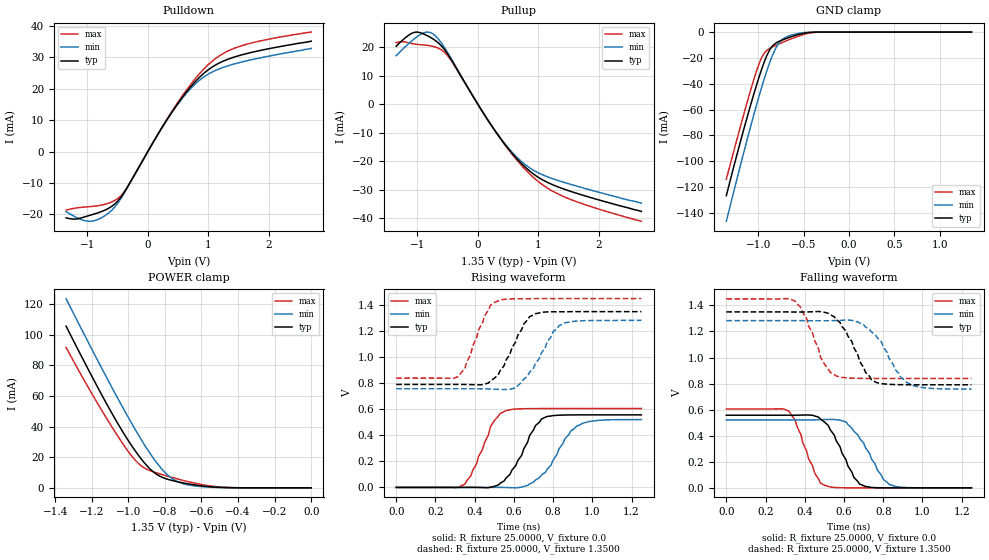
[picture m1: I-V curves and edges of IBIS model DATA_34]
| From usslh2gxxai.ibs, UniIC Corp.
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|When TDQS is enabled, NU_TDQS is a output with terminal resistance;
|When TDQS is disabled, NU_TDQS is a DM;
|   Model DATA_34
[Model]  DATA_34
Model_type I/O
Polarity   Non-Inverting
Enable   Active-High
Vinl =   0.54000000V
Vinh =   0.81000000V
Vmeas =   0.67500000V
Rref =   25.00000000
Vref =   0.67500000V
C_comp   1.6290pF   1.6100pF   1.6540pF
[Temperature Range]   25.0000   95.0000   -40.0
[Voltage Range]   1.3500V   1.2830V   1.4500V
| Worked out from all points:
|   slope of the pulldown table from 0 to 0.203 V, typ, clamps not added: 30.6 ohm
|   slope of the pullup table from 0 to 0.203 V, typ, clamps not added: 29.9 ohm
|   GND clamp passes 1 mA (typ) near -0.50 V on its own axis
|   POWER clamp passes 1 mA (typ) near -0.58 V on its own axis
|   rising waveform, R_fixture 25.0000, V_fixture 0.0: 20-80 % time 118ps typ, 135ps min, 101ps max; typ from 0 V to 0.557 V
|   rising waveform, R_fixture 25.0000, V_fixture 1.3500: 20-80 % time 113ps typ, 123ps min, 96ps max; typ from 0.791 V to 1.35 V
|   falling waveform, R_fixture 25.0000, V_fixture 0.0: 20-80 % time 113ps typ, 123ps min, 91.3ps max; typ from 0.557 V to 0 V
|   falling waveform, R_fixture 25.0000, V_fixture 1.3500: 20-80 % time 116ps typ, 127ps min, 98.9ps max; typ from 1.35 V to 0.791 V
[Pulldown]
|Voltage   I(typ)   I(min)   I(max)
-1.35V    -21.1mA    -19.1mA    -18.6mA
-950mV    -20.24mA   -22.17mA   -17.5mA
-600mV    -17.48mA   -18.77mA   -16.07mA
-450mV    -14.7mA    -15.11mA   -14.18mA
-350mV    -11.73mA   -11.85mA   -11.7mA
150mV     4.943mA    4.94mA     5.014mA
450mV     14mA       13.86mA    14.33mA
750mV     21.51mA    20.87mA    22.36mA
1V        26.03mA    24.64mA    27.65mA
1.25V     28.79mA    26.8mA     31.23mA
1.55V     30.74mA    28.48mA    33.65mA
2.7V      35.1mA     32.8mA     38.01mA
[Pullup]
|Voltage   I(typ)   I(min)   I(max)
-1.35V    20.4mA     17.1mA     21.67mA
-1.05V    25.31mA    23.05mA    21.21mA
-900mV    24.74mA    25.1mA     20.86mA
-750mV    23.1mA     24.86mA    20.41mA
-600mV    20.47mA    21.48mA    19.1mA
-500mV    17.69mA    18.18mA    17.09mA
250mV     -8.265mA   -8.209mA   -8.313mA
500mV     -15.52mA   -15.24mA   -15.77mA
750mV     -21.44mA   -20.63mA   -22.15mA
1.05V     -26.3mA    -24.57mA   -27.98mA
1.35V     -29.2mA    -26.91mA   -31.75mA
2.7V      -37.6mA    -34.7mA    -41.06mA
[GND_clamp]
|Voltage   I(typ)   I(min)   I(max)
-1.35V    -126.6mA   -146.4mA   -113.9mA
-1.23V    -94.01mA   -112.8mA   -82.22mA
-1.11V    -63.21mA   -80.3mA    -51.66mA
-990mV    -34.91mA   -49.67mA   -24.67mA
-930mV    -22.66mA   -35.65mA   -16.03mA
-870mV    -13.47mA   -23.14mA   -12.51mA
-810mV    -8.797mA   -13.1mA    -10.48mA
-780mV    -7.577mA   -9.433mA   -9.536mA
-720mV    -5.772mA   -5.033mA   -7.705mA
-570mV    -2.205mA   -1.261mA   -3.537mA
-360mV    -62.74uA   -23.25uA   -177uA
1.35V     3.66nA     11.73nA    2.588nA
[POWER_clamp]
|Voltage   I(typ)   I(min)   I(max)
-1.34V    105.5mA    123.5mA    91.69mA
-1.14V    59.56mA    76.88mA    49.59mA
-1.06V    42.52mA    58.94mA    34.24mA
-980mV    27.22mA    41.75mA    20.57mA
-940mV    20.5mA     33.6mA     15.4mA
-880mV    12.18mA    22.27mA    11.15mA
-840mV    8.415mA    15.63mA    9.537mA
-780mV    5.408mA    7.848mA    7.429mA
-700mV    3.206mA    2.693mA    4.858mA
-600mV    1.29mA     794.5uA    2.191mA
-440mV    104.5uA    65.08uA    176.8uA
0V        3.66nA     5.436nA    3.157nA
[Ramp]
| variable   typ   min   max
dV/dt_r  0.3343/0.1169n   0.3127/0.1346n   0.3633/99.5040p
dV/dt_f  0.3356/0.1137n   0.3152/0.1290n   0.3664/96.6842p
R_load = 25.0000
[Rising Waveform]
R_fixture= 25.0000
V_fixture= 0.0
V_fixture_min= 0.0
V_fixture_max= 0.0
|time   V(typ)   V(min)   V(max)
0s        0V         0V         0V
350ps     125uV      -9.171uV   25.1mV
410ps     117.4uV    74.84uV    181.9mV
480ps     1.386mV    338.8uV    464.1mV
560ps     71.89mV    -749.3uV   590.4mV
640ps     247.6mV    2.237mV    603.9mV
710ps     474.8mV    56.97mV    605.3mV
760ps     539.1mV    115.7mV    605.5mV
920ps     557mV      470.3mV    605.5mV
1.25ns    557.2mV    521.1mV    605.5mV
[Rising Waveform]
R_fixture= 25.0000
V_fixture= 1.3500
V_fixture_min= 1.2830
V_fixture_max= 1.4500
|time   V(typ)   V(min)   V(max)
0s        790.7mV    757.6mV    839.4mV
320ps     790.8mV    757.6mV    854.2mV
450ps     793mV      756.5mV    1.315V
530ps     897.2mV    752.2mV    1.44V
610ps     1.12V      763.8mV    1.449V
650ps     1.254V     830.7mV    1.449V
710ps     1.334V     952.5mV    1.45V
800ps     1.349V     1.195V     1.45V
860ps     1.349V     1.264V     1.45V
1.25ns    1.35V      1.283V     1.45V
[Falling Waveform]
R_fixture= 25.0000
V_fixture= 0.0
V_fixture_min= 0.0
V_fixture_max= 0.0
|time   V(typ)   V(min)   V(max)
0s        557.2mV    521.1mV    605.5mV
320ps     557.1mV    521mV      586.4mV
350ps     557.3mV    521mV      523.6mV
450ps     551.7mV    521.8mV    115.3mV
500ps     505.5mV    524mV      20.07mV
550ps     405.6mV    524.5mV    3.427mV
610ps     216mV      506mV      351.2uV
680ps     28.48mV    378.3mV    19.89uV
830ps     108.3uV    26.34mV    0V
1.25ns    0V         0V         0V
[Falling Waveform]
R_fixture= 25.0000
V_fixture= 1.3500
V_fixture_min= 1.2830
V_fixture_max= 1.4500
|time   V(typ)   V(min)   V(max)
0s        1.35V      1.283V     1.45V
350ps     1.349V     1.283V     1.434V
410ps     1.35V      1.282V     1.297V
480ps     1.352V     1.282V     1.003V
560ps     1.293V     1.284V     858.4mV
670ps     1.023V     1.274V     840.2mV
710ps     885.4mV    1.234V     839.6mV
760ps     812.2mV    1.175V     839.4mV
920ps     791mV      808mV      839.4mV
1.25ns    790.7mV    757.7mV    839.4mV
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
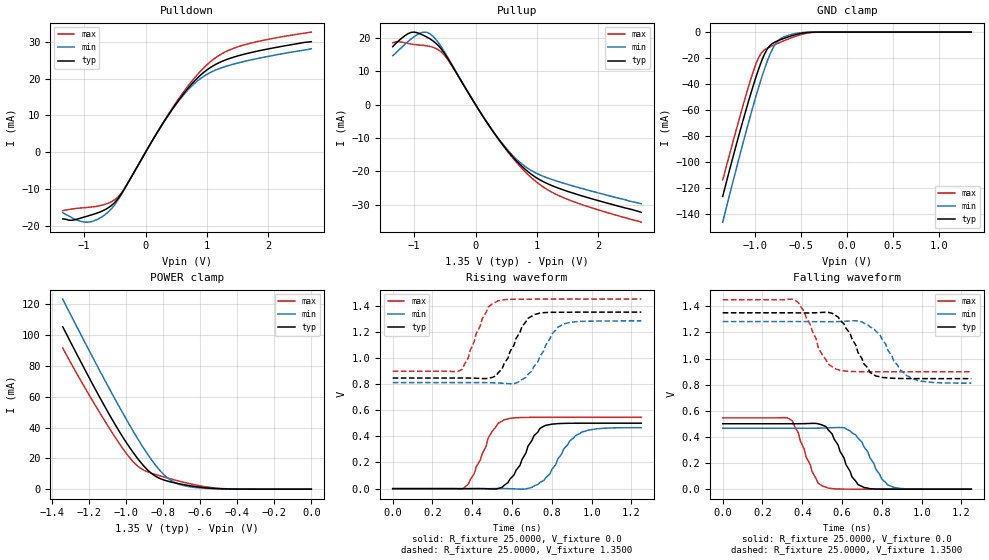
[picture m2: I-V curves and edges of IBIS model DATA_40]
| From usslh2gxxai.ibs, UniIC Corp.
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|   Model DATA_40
[Model]  DATA_40
Model_type I/O
Polarity   Non-Inverting
Enable   Active-High
Vinl =   0.54000000V
Vinh =   0.81000000V
Vmeas =   0.67500000V
Rref =   25.00000000
Vref =   0.67500000V
C_comp   1.6290pF   1.6100pF   1.6540pF
[Temperature Range]   25.0000   95.0000   -40.0
[Voltage Range]   1.3500V   1.2830V   1.4500V
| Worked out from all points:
|   slope of the pulldown table from 0 to 0.203 V, typ, clamps not added: 35.6 ohm
|   slope of the pullup table from 0 to 0.203 V, typ, clamps not added: 34.8 ohm
|   GND clamp passes 1 mA (typ) near -0.50 V on its own axis
|   POWER clamp passes 1 mA (typ) near -0.58 V on its own axis
|   rising waveform, R_fixture 25.0000, V_fixture 0.0: 20-80 % time 102ps typ, 120ps min, 91.5ps max; typ from 0 V to 0.501 V
|   rising waveform, R_fixture 25.0000, V_fixture 1.3500: 20-80 % time 97.2ps typ, 102ps min, 85ps max; typ from 0.846 V to 1.35 V
|   falling waveform, R_fixture 25.0000, V_fixture 0.0: 20-80 % time 93ps typ, 104ps min, 80.7ps max; typ from 0.501 V to 0 V
|   falling waveform, R_fixture 25.0000, V_fixture 1.3500: 20-80 % time 103ps typ, 113ps min, 95.7ps max; typ from 1.35 V to 0.846 V
[Pulldown]
|Voltage   I(typ)   I(min)   I(max)
-1.35V    -18.1mA    -16.4mA    -15.9mA
-1.2V     -18.48mA   -17.8mA    -15.42mA
-950mV    -17.36mA   -19mA      -15mA
-600mV    -15mA      -16.12mA   -13.79mA
-350mV    -10.09mA   -10.2mA    -10.06mA
150mV     4.251mA    4.248mA    4.312mA
450mV     12.04mA    11.91mA    12.32mA
750mV     18.48mA    17.93mA    19.21mA
1V        22.35mA    21.14mA    23.74mA
1.25V     24.7mA     22.99mA    26.8mA
1.5V      26.13mA    24.21mA    28.6mA
2.7V      30mA       28.1mA     32.61mA
[Pullup]
|Voltage   I(typ)   I(min)   I(max)
-1.35V    17.4mA     14.7mA     18.57mA
-1.05V    21.68mA    19.73mA    18.19mA
-900mV    21.23mA    21.49mA    17.88mA
-750mV    19.83mA    21.34mA    17.51mA
-650mV    18.49mA    19.64mA    16.9mA
-500mV    15.23mA    15.64mA    14.69mA
250mV     -7.107mA   -7.058mA   -7.148mA
500mV     -13.34mA   -13.09mA   -13.56mA
750mV     -18.41mA   -17.72mA   -19.03mA
1.05V     -22.57mA   -21.08mA   -24.02mA
1.35V     -25.05mA   -23.08mA   -27.24mA
2.7V      -32.3mA    -29.7mA    -35.26mA
[GND_clamp]
|Voltage   I(typ)   I(min)   I(max)
-1.35V    -126.6mA   -146.4mA   -113.9mA
-1.23V    -94.01mA   -112.8mA   -82.22mA
-1.11V    -63.21mA   -80.3mA    -51.66mA
-990mV    -34.91mA   -49.67mA   -24.67mA
-930mV    -22.66mA   -35.65mA   -16.03mA
-870mV    -13.47mA   -23.14mA   -12.51mA
-810mV    -8.797mA   -13.1mA    -10.48mA
-780mV    -7.577mA   -9.433mA   -9.536mA
-720mV    -5.772mA   -5.033mA   -7.705mA
-570mV    -2.205mA   -1.261mA   -3.537mA
-360mV    -62.74uA   -23.25uA   -177uA
1.35V     3.66nA     11.73nA    2.588nA
[POWER_clamp]
|Voltage   I(typ)   I(min)   I(max)
-1.34V    105.5mA    123.5mA    91.69mA
-1.14V    59.56mA    76.88mA    49.59mA
-1.06V    42.52mA    58.94mA    34.24mA
-980mV    27.22mA    41.75mA    20.57mA
-940mV    20.5mA     33.6mA     15.4mA
-880mV    12.18mA    22.27mA    11.15mA
-840mV    8.415mA    15.63mA    9.537mA
-780mV    5.408mA    7.848mA    7.429mA
-700mV    3.206mA    2.693mA    4.858mA
-600mV    1.29mA     794.5uA    2.191mA
-440mV    104.5uA    65.08uA    176.8uA
0V        3.66nA     5.436nA    3.157nA
[Ramp]
| variable   typ   min   max
dV/dt_r  0.3005/0.1058n   0.2799/0.1203n   0.3274/91.1319p
dV/dt_f  0.3023/0.1041n   0.2831/0.1145n   0.3310/90.9841p
R_load = 25.0000
[Rising Waveform]
R_fixture= 25.0000
V_fixture= 0.0
V_fixture_min= 0.0
V_fixture_max= 0.0
|time   V(typ)   V(min)   V(max)
0s        0V         0V         0V
350ps     -168.2nV   -8.579uV   -3.913mV
410ps     276.8uV    -7.005uV   114.3mV
500ps     -2.724mV   240uV      438.4mV
560ps     24.84mV    483.6uV    526.5mV
640ps     178mV      -3.699mV   543.5mV
710ps     404.5mV    19.98mV    545.5mV
770ps     484.8mV    84.21mV    545.7mV
950ps     500.7mV    432.1mV    545.7mV
1.25ns    500.8mV    466.5mV    545.7mV
[Rising Waveform]
R_fixture= 25.0000
V_fixture= 1.3500
V_fixture_min= 1.2830
V_fixture_max= 1.4500
|time   V(typ)   V(min)   V(max)
0s        846.1mV    811.2mV    898.4mV
350ps     846.3mV    811.2mV    912.8mV
480ps     844.1mV    810.3mV    1.388V
530ps     885.5mV    807.8mV    1.437V
640ps     1.196V     821.1mV    1.449V
680ps     1.303V     873.7mV    1.449V
710ps     1.331V     934mV      1.45V
800ps     1.349V     1.183V     1.45V
860ps     1.349V     1.26V      1.45V
1.25ns    1.35V      1.283V     1.45V
[Falling Waveform]
R_fixture= 25.0000
V_fixture= 0.0
V_fixture_min= 0.0
V_fixture_max= 0.0
|time   V(typ)   V(min)   V(max)
0s        500.8mV    466.5mV    545.7mV
350ps     500.7mV    466.5mV    523.5mV
480ps     499.8mV    467.1mV    45.44mV
530ps     454.8mV    469.3mV    8.298mV
580ps     338.1mV    472mV      1.599mV
650ps     94.15mV    431.4mV    104.9uV
710ps     12.71mV    324.5mV    11.19uV
800ps     404.9uV    76.66mV    0V
860ps     61.5uV     13.66mV    0V
1.25ns    0V         0V         0V
[Falling Waveform]
R_fixture= 25.0000
V_fixture= 1.3500
V_fixture_min= 1.2830
V_fixture_max= 1.4500
|time   V(typ)   V(min)   V(max)
0s        1.35V      1.283V     1.45V
360ps     1.35V      1.283V     1.449V
410ps     1.349V     1.283V     1.361V
530ps     1.353V     1.282V     957.5mV
590ps     1.294V     1.283V     909.4mV
710ps     959.3mV    1.27V      898.8mV
770ps     866.2mV    1.209V     898.5mV
890ps     847.2mV    916.4mV    898.4mV
950ps     846.4mV    846.7mV    898.4mV
1.25ns    846.1mV    811.3mV    898.4mV
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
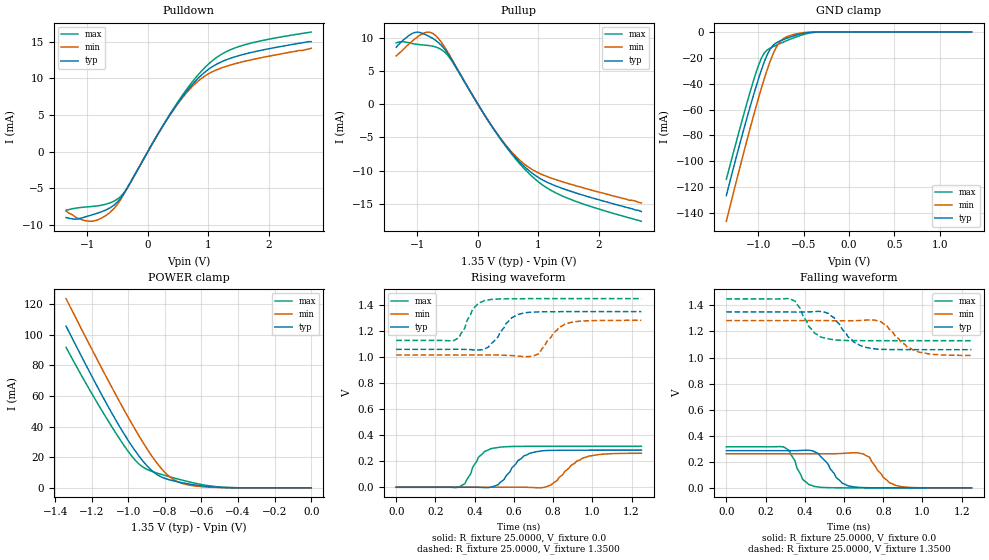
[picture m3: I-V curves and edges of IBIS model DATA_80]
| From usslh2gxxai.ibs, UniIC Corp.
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|   Model DATA_80
[Model]  DATA_80
Model_type I/O
Polarity   Non-Inverting
Enable   Active-High
Vinl =   0.54000000V
Vinh =   0.81000000V
Vmeas =   0.67500000V
Rref =   25.00000000
Vref =   0.67500000V
C_comp   1.6290pF   1.6100pF   1.6540pF
[Temperature Range]   25.0000   95.0000   -40.0
[Voltage Range]   1.3500V   1.2830V   1.4500V
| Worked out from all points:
|   slope of the pulldown table from 0 to 0.203 V, typ, clamps not added: 70.5 ohm
|   slope of the pullup table from 0 to 0.203 V, typ, clamps not added: 69 ohm
|   GND clamp passes 1 mA (typ) near -0.50 V on its own axis
|   POWER clamp passes 1 mA (typ) near -0.58 V on its own axis
|   rising waveform, R_fixture 25.0000, V_fixture 0.0: 20-80 % time 95.1ps typ, 114ps min, 74.2ps max; typ from 0 V to 0.285 V
|   rising waveform, R_fixture 25.0000, V_fixture 1.3500: 20-80 % time 88.7ps typ, 85.8ps min, 65.6ps max; typ from 1.06 V to 1.35 V
|   falling waveform, R_fixture 25.0000, V_fixture 0.0: 20-80 % time 88.5ps typ, 85ps min, 59.4ps max; typ from 0.285 V to 0 V
|   falling waveform, R_fixture 25.0000, V_fixture 1.3500: 20-80 % time 95ps typ, 116ps min, 75.3ps max; typ from 1.35 V to 1.06 V
[Pulldown]
|Voltage   I(typ)   I(min)   I(max)
-1.35V    -9mA       -8.1mA     -8mA
-1.2V     -9.22mA    -8.9mA     -7.72mA
-950mV    -8.7mA     -9.5mA     -7.5mA
-600mV    -7.532mA   -8.104mA   -6.913mA
-350mV    -5.095mA   -5.151mA   -5.075mA
150mV     2.146mA    2.145mA    2.177mA
450mV     6.069mA    6.003mA    6.212mA
750mV     9.3mA      9.014mA    9.676mA
1V        11.22mA    10.61mA    11.93mA
1.25V     12.38mA    11.52mA    13.44mA
1.55V     13.2mA     12.23mA    14.46mA
2.7V      15mA       14.1mA     16.32mA
[Pullup]
|Voltage   I(typ)   I(min)   I(max)
-1.35V    8.6mA      7.3mA      9.27mA
-1.05V    10.82mA    9.81mA     9.1mA
-900mV    10.64mA    10.72mA    8.94mA
-750mV    9.959mA    10.72mA    8.768mA
-650mV    9.3mA      9.895mA    8.473mA
-500mV    7.685mA    7.906mA    7.405mA
250mV     -3.587mA   -3.562mA   -3.608mA
500mV     -6.724mA   -6.596mA   -6.835mA
750mV     -9.264mA   -8.906mA   -9.58mA
1.05V     -11.33mA   -10.57mA   -12.07mA
1.4V      -12.72mA   -11.71mA   -13.87mA
2.7V      -16.2mA    -14.9mA    -17.66mA
[GND_clamp]
|Voltage   I(typ)   I(min)   I(max)
-1.35V    -126.6mA   -146.4mA   -113.9mA
-1.23V    -94.01mA   -112.8mA   -82.22mA
-1.11V    -63.21mA   -80.3mA    -51.66mA
-990mV    -34.91mA   -49.67mA   -24.67mA
-930mV    -22.66mA   -35.65mA   -16.03mA
-870mV    -13.47mA   -23.14mA   -12.51mA
-810mV    -8.797mA   -13.1mA    -10.48mA
-780mV    -7.577mA   -9.433mA   -9.536mA
-720mV    -5.772mA   -5.033mA   -7.705mA
-570mV    -2.205mA   -1.261mA   -3.537mA
-360mV    -62.74uA   -23.25uA   -177uA
1.35V     3.66nA     11.73nA    2.588nA
[POWER_clamp]
|Voltage   I(typ)   I(min)   I(max)
-1.34V    105.5mA    123.5mA    91.69mA
-1.14V    59.56mA    76.88mA    49.59mA
-1.06V    42.52mA    58.94mA    34.24mA
-980mV    27.22mA    41.75mA    20.57mA
-940mV    20.5mA     33.6mA     15.4mA
-880mV    12.18mA    22.27mA    11.15mA
-840mV    8.415mA    15.63mA    9.537mA
-780mV    5.408mA    7.848mA    7.429mA
-700mV    3.206mA    2.693mA    4.858mA
-600mV    1.29mA     794.5uA    2.191mA
-440mV    104.5uA    65.08uA    176.8uA
0V        3.66nA     5.436nA    3.157nA
[Ramp]
| variable   typ   min   max
dV/dt_r  0.1711/95.8702p   0.1568/0.1150n   0.1889/70.6281p
dV/dt_f  0.1740/97.5000p   0.1602/0.1134n   0.1926/76.8497p
R_load = 25.0000
[Rising Waveform]
R_fixture= 25.0000
V_fixture= 0.0
V_fixture_min= 0.0
V_fixture_max= 0.0
|time   V(typ)   V(min)   V(max)
0s        0V         0V         0V
320ps     28.4uV     0V         566.4uV
350ps     147.1uV    0V         27.35mV
420ps     -395uV     -6.871uV   231.9mV
500ps     7.999mV    19.25uV    301.7mV
620ps     203.4mV    449.6uV    314.2mV
710ps     272.5mV    -3.187mV   314.8mV
790ps     283.4mV    17.6mV     314.9mV
980ps     285mV      238.6mV    314.9mV
1.25ns    285.1mV    261.3mV    314.9mV
[Rising Waveform]
R_fixture= 25.0000
V_fixture= 1.3500
V_fixture_min= 1.2830
V_fixture_max= 1.4500
|time   V(typ)   V(min)   V(max)
0s        1.06V      1.016V     1.129V
290ps     1.061V     1.016V     1.126V
320ps     1.061V     1.016V     1.15V
390ps     1.056V     1.016V     1.37V
480ps     1.097V     1.016V     1.443V
590ps     1.304V     1.012V     1.449V
650ps     1.34V      1.004V     1.449V
730ps     1.348V     1.028V     1.45V
860ps     1.35V      1.254V     1.45V
1.25ns    1.35V      1.283V     1.45V
[Falling Waveform]
R_fixture= 25.0000
V_fixture= 0.0
V_fixture_min= 0.0
V_fixture_max= 0.0
|time   V(typ)   V(min)   V(max)
0s        285.1mV    261.4mV    314.9mV
290ps     285mV      261.4mV    315mV
320ps     284.8mV    261.4mV    287.5mV
390ps     287.8mV    261.3mV    63.36mV
450ps     276.3mV    261.2mV    10.3mV
620ps     15.58mV    267.3mV    71.96uV
730ps     785.6uV    235.2mV    2.735uV
800ps     64.2uV     80.46mV    0V
860ps     11.7uV     19.72mV    0V
1.25ns    0V         0V         0V
[Falling Waveform]
R_fixture= 25.0000
V_fixture= 1.3500
V_fixture_min= 1.2830
V_fixture_max= 1.4500
|time   V(typ)   V(min)   V(max)
0s        1.35V      1.283V     1.45V
320ps     1.35V      1.283V     1.452V
350ps     1.349V     1.283V     1.433V
450ps     1.353V     1.283V     1.187V
530ps     1.324V     1.282V     1.14V
650ps     1.118V     1.283V     1.13V
710ps     1.078V     1.287V     1.129V
790ps     1.063V     1.273V     1.129V
980ps     1.06V      1.042V     1.129V
1.25ns    1.06V      1.016V     1.129V
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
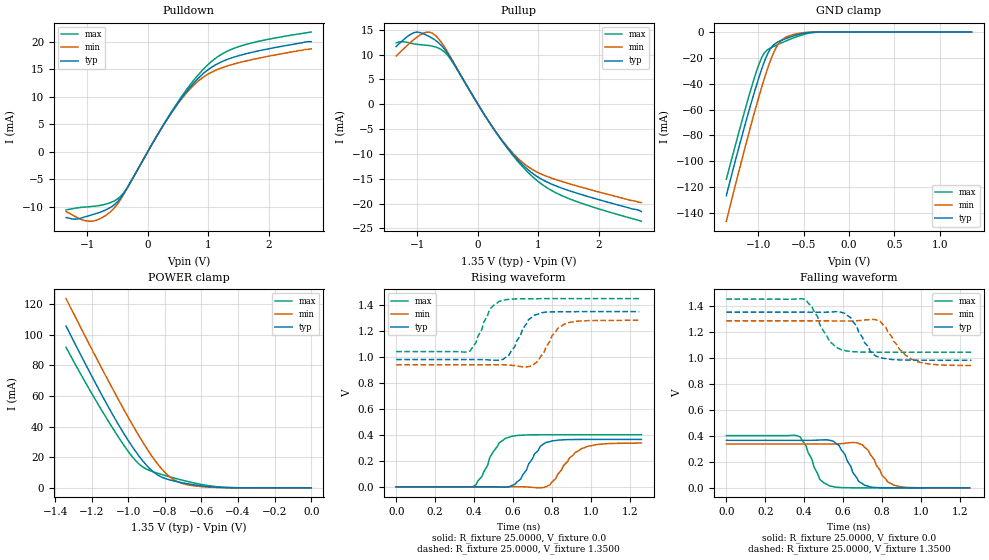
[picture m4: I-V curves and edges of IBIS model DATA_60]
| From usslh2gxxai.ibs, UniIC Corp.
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|   Model DATA_60
[Model]  DATA_60
Model_type I/O
Polarity   Non-Inverting
Enable   Active-High
Vinl =   0.54000000V
Vinh =   0.81000000V
Vmeas =   0.67500000V
Rref =   25.00000000
Vref =   0.67500000V
C_comp   1.6290pF   1.6100pF   1.6540pF
[Temperature Range]   25.0000   95.0000   -40.0
[Voltage Range]   1.3500V   1.2830V   1.4500V
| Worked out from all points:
|   slope of the pulldown table from 0 to 0.203 V, typ, clamps not added: 53.1 ohm
|   slope of the pullup table from 0 to 0.203 V, typ, clamps not added: 51.9 ohm
|   GND clamp passes 1 mA (typ) near -0.50 V on its own axis
|   POWER clamp passes 1 mA (typ) near -0.58 V on its own axis
|   rising waveform, R_fixture 25.0000, V_fixture 0.0: 20-80 % time 89.5ps typ, 106ps min, 82.8ps max; typ from 0 V to 0.365 V
|   rising waveform, R_fixture 25.0000, V_fixture 1.3500: 20-80 % time 80.5ps typ, 82.1ps min, 68.4ps max; typ from 0.98 V to 1.35 V
|   falling waveform, R_fixture 25.0000, V_fixture 0.0: 20-80 % time 81.1ps typ, 84.2ps min, 66.2ps max; typ from 0.365 V to 0 V
|   falling waveform, R_fixture 25.0000, V_fixture 1.3500: 20-80 % time 86.7ps typ, 107ps min, 84.3ps max; typ from 1.35 V to 0.98 V
[Pulldown]
|Voltage   I(typ)   I(min)   I(max)
-1.35V    -12mA      -10.9mA    -10.6mA
-1.2V     -12.29mA   -11.8mA    -10.29mA
-950mV    -11.59mA   -12.67mA   -10mA
-600mV    -10.03mA   -10.79mA   -9.203mA
-450mV    -8.463mA   -8.711mA   -8.15mA
-350mV    -6.771mA   -6.844mA   -6.746mA
150mV     2.852mA    2.85mA     2.893mA
450mV     8.069mA    7.982mA    8.258mA
750mV     12.37mA    12mA       12.87mA
1V        14.94mA    14.13mA    15.88mA
1.5V      17.44mA    16.16mA    19.09mA
2.7V      20mA       18.7mA     21.75mA
[Pullup]
|Voltage   I(typ)   I(min)   I(max)
-1.35V    11.6mA     9.7mA      12.37mA
-1.05V    14.44mA    13.1mA     12.13mA
-900mV    14.18mA    14.31mA    11.92mA
-750mV    13.26mA    14.27mA    11.68mA
-650mV    12.37mA    13.16mA    11.29mA
-500mV    10.22mA    10.5mA     9.845mA
250mV     -4.768mA   -4.734mA   -4.796mA
500mV     -8.941mA   -8.773mA   -9.088mA
750mV     -12.33mA   -11.85mA   -12.74mA
1.05V     -15.08mA   -14.08mA   -16.06mA
1.4V      -16.95mA   -15.6mA    -18.47mA
2.7V      -21.6mA    -19.8mA    -23.56mA
[GND_clamp]
|Voltage   I(typ)   I(min)   I(max)
-1.35V    -126.6mA   -146.4mA   -113.9mA
-1.23V    -94.01mA   -112.8mA   -82.22mA
-1.11V    -63.21mA   -80.3mA    -51.66mA
-990mV    -34.91mA   -49.67mA   -24.67mA
-930mV    -22.66mA   -35.65mA   -16.03mA
-870mV    -13.47mA   -23.14mA   -12.51mA
-810mV    -8.797mA   -13.1mA    -10.48mA
-780mV    -7.577mA   -9.433mA   -9.536mA
-720mV    -5.772mA   -5.033mA   -7.705mA
-570mV    -2.205mA   -1.261mA   -3.537mA
-360mV    -62.74uA   -23.25uA   -177uA
1.35V     3.66nA     11.73nA    2.588nA
[POWER_clamp]
|Voltage   I(typ)   I(min)   I(max)
-1.34V    105.5mA    123.5mA    91.69mA
-1.14V    59.56mA    76.88mA    49.59mA
-1.06V    42.52mA    58.94mA    34.24mA
-980mV    27.22mA    41.75mA    20.57mA
-940mV    20.5mA     33.6mA     15.4mA
-880mV    12.18mA    22.27mA    11.15mA
-840mV    8.415mA    15.63mA    9.537mA
-780mV    5.408mA    7.848mA    7.429mA
-700mV    3.206mA    2.693mA    4.858mA
-600mV    1.29mA     794.5uA    2.191mA
-440mV    104.5uA    65.08uA    176.8uA
0V        3.66nA     5.436nA    3.157nA
[Ramp]
| variable   typ   min   max
dV/dt_r  0.2191/91.3875p   0.2020/0.1080n   0.2408/79.1756p
dV/dt_f  0.2217/91.5243p   0.2057/0.1059n   0.2448/80.6023p
R_load = 25.0000
[Rising Waveform]
R_fixture= 25.0000
V_fixture= 0.0
V_fixture_min= 0.0
V_fixture_max= 0.0
|time   V(typ)   V(min)   V(max)
0s        0V         0V         0V
390ps     -5.094uV   -1.669uV   -2.276mV
440ps     146.2uV    -14.92uV   78.02mV
530ps     -1.175mV   82.15uV    339.7mV
580ps     524.6uV    386.4uV    382mV
640ps     59.46mV    491.2uV    397.2mV
710ps     251.2mV    -5.999mV   400.7mV
760ps     332.9mV    -5.287mV   401.2mV
950ps     364.8mV    292.9mV    401.3mV
1.26ns    365.2mV    337.3mV    401.3mV
[Rising Waveform]
R_fixture= 25.0000
V_fixture= 1.3500
V_fixture_min= 1.2830
V_fixture_max= 1.4500
|time   V(typ)   V(min)   V(max)
0s        980.5mV    940mV      1.042V
380ps     980.6mV    940mV      1.047V
480ps     977mV      940.4mV    1.367V
560ps     994.6mV    939.4mV    1.441V
610ps     1.081V     934.2mV    1.447V
680ps     1.288V     925.9mV    1.449V
740ps     1.339V     998.6mV    1.45V
800ps     1.348V     1.162V     1.45V
860ps     1.349V     1.251V     1.45V
1.25ns    1.35V      1.283V     1.45V
[Falling Waveform]
R_fixture= 25.0000
V_fixture= 0.0
V_fixture_min= 0.0
V_fixture_max= 0.0
|time   V(typ)   V(min)   V(max)
0s        365.2mV    336.7mV    401.3mV
380ps     365.1mV    336.7mV    391.2mV
480ps     367.6mV    336.3mV    65.15mV
530ps     365.8mV    336.1mV    14.79mV
580ps     324mV      337.9mV    3.433mV
650ps     117.8mV    348.4mV    303.5uV
710ps     20.31mV    312.6mV    42.89uV
800ps     868uV      97.17mV    1.055uV
860ps     145.1uV    20.6mV     0V
1.25ns    0V         0V         0V
[Falling Waveform]
R_fixture= 25.0000
V_fixture= 1.3500
V_fixture_min= 1.2830
V_fixture_max= 1.4500
|time   V(typ)   V(min)   V(max)
0s        1.35V      1.283V     1.45V
410ps     1.35V      1.283V     1.444V
530ps     1.351V     1.283V     1.125V
590ps     1.349V     1.282V     1.062V
640ps     1.306V     1.282V     1.048V
760ps     1.022V     1.294V     1.042V
820ps     992.3mV    1.233V     1.042V
890ps     982.8mV    1.064V     1.042V
950ps     981.1mV    988.9mV    1.042V
1.26ns    980.5mV    940.1mV    1.042V
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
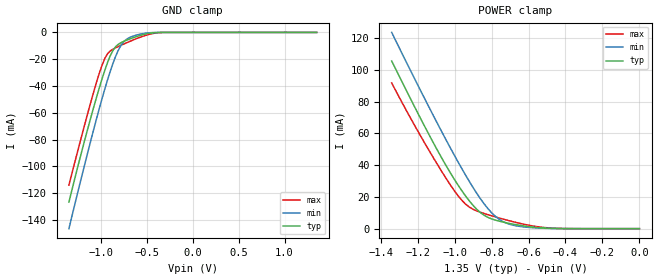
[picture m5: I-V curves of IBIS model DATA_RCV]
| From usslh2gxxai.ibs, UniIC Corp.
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|   Model DATA_RCV
[Model]  DATA_RCV
Model_type Input
Vinl =   0.54000000V
Vinh =   0.81000000V
C_comp   1.6290pF   1.6100pF   1.6540pF
[Temperature Range]   25.0000   95.0000   -40.0
[Voltage Range]   1.3500V   1.2830V   1.4500V
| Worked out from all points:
|   GND clamp passes 1 mA (typ) near -0.50 V on its own axis
|   POWER clamp passes 1 mA (typ) near -0.58 V on its own axis
[GND_clamp]
|Voltage   I(typ)   I(min)   I(max)
-1.35V    -126.6mA   -146.4mA   -113.9mA
-1.23V    -94.01mA   -112.8mA   -82.22mA
-1.11V    -63.21mA   -80.3mA    -51.66mA
-990mV    -34.91mA   -49.67mA   -24.67mA
-930mV    -22.66mA   -35.65mA   -16.03mA
-870mV    -13.47mA   -23.14mA   -12.51mA
-810mV    -8.797mA   -13.1mA    -10.48mA
-780mV    -7.577mA   -9.433mA   -9.536mA
-720mV    -5.772mA   -5.033mA   -7.705mA
-570mV    -2.205mA   -1.261mA   -3.537mA
-360mV    -62.74uA   -23.25uA   -177uA
1.35V     3.66nA     11.73nA    2.588nA
[POWER_clamp]
|Voltage   I(typ)   I(min)   I(max)
-1.34V    105.5mA    123.5mA    91.69mA
-1.14V    59.56mA    76.88mA    49.59mA
-1.06V    42.52mA    58.94mA    34.24mA
-980mV    27.22mA    41.75mA    20.57mA
-940mV    20.5mA     33.6mA     15.4mA
-880mV    12.18mA    22.27mA    11.15mA
-840mV    8.415mA    15.63mA    9.537mA
-780mV    5.408mA    7.848mA    7.429mA
-700mV    3.206mA    2.693mA    4.858mA
-600mV    1.29mA     794.5uA    2.191mA
-440mV    104.5uA    65.08uA    176.8uA
0V        3.66nA     5.436nA    3.157nA
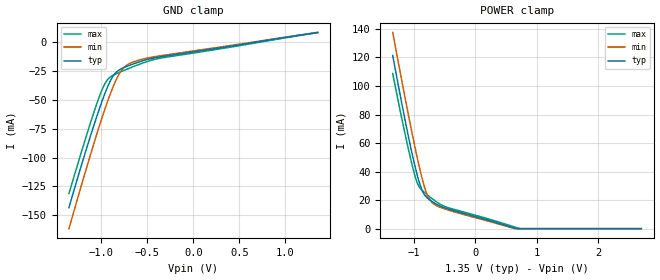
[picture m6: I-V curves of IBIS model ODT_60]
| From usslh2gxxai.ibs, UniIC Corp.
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|   Model ODT_60
[Model]  ODT_60
Model_type Input
Vinl =   0.54000000V
Vinh =   0.81000000V
C_comp   1.6290pF   1.6100pF   1.6540pF
[Temperature Range]   25.0000   95.0000   -40.0
[Voltage Range]   1.3500V   1.2800V   1.4500V
[GND_clamp]
|Voltage   I(typ)   I(min)   I(max)
-1.35V    -143.4mA   -161.6mA   -131.1mA
-1.23V    -110.7mA   -128.2mA   -99.14mA
-1.11V    -79.66mA   -95.84mA   -68.28mA
-990mV    -50.97mA   -65.2mA    -41.03mA
-930mV    -38.52mA   -51.1mA    -32.26mA
-870mV    -29.14mA   -38.44mA   -28.6mA
-810mV    -24.26mA   -28.19mA   -26.42mA
-780mV    -22.93mA   -24.4mA    -25.4mA
-720mV    -20.89mA   -19.73mA   -23.39mA
-570mV    -16.6mA    -15.05mA   -18.67mA
-360mV    -12.67mA   -11.75mA   -13.84mA
1.35V     8.47mA     8.53mA     8.249mA
[POWER_clamp]
|Voltage   I(typ)   I(min)   I(max)
-1.34V    121.4mA    137.6mA    108.8mA
-1.1V     67.77mA    83.12mA    58.68mA
-1.02V    51.59mA    65.83mA    43.79mA
-960mV    40.68mA    53.44mA    34.4mA
-920mV    34.24mA    45.6mA     30.12mA
-880mV    28.83mA    38.26mA    27.66mA
-800mV    22.5mA     26.06mA    24.5mA
-740mV    20.27mA    20.35mA    22.37mA
-680mV    18.51mA    17.5mA     20.36mA
-440mV    13.79mA    13.04mA    14.74mA
675mV     0A         NA         NA
2.7V      0A         0A         0A
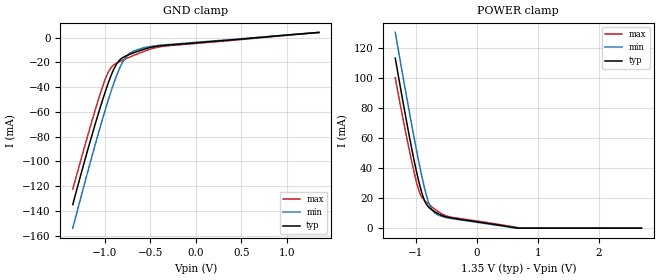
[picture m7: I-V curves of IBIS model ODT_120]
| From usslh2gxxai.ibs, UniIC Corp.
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|   Model ODT_120
[Model]  ODT_120
Model_type Input
Vinl =   0.54000000V
Vinh =   0.81000000V
C_comp   1.6290pF   1.6100pF   1.6540pF
[Temperature Range]   25.0000   95.0000   -40.0
[Voltage Range]   1.3500V   1.2830V   1.4500V
[GND_clamp]
|Voltage   I(typ)   I(min)   I(max)
-1.35V    -135mA     -154mA     -122.5mA
-1.11V    -71.44mA   -88.11mA   -59.98mA
-1.05V    -56.79mA   -72.47mA   -45.59mA
-990mV    -42.94mA   -57.47mA   -32.86mA
-930mV    -30.6mA    -43.41mA   -24.14mA
-870mV    -21.31mA   -30.83mA   -20.56mA
-810mV    -16.53mA   -20.68mA   -18.45mA
-780mV    -15.26mA   -16.96mA   -17.47mA
-720mV    -13.34mA   -12.42mA   -15.55mA
-570mV    -9.41mA    -8.197mA   -11.11mA
-360mV    -6.373mA   -5.927mA   -7.017mA
1.35V     4.238mA    4.275mA    4.127mA
[POWER_clamp]
|Voltage   I(typ)   I(min)   I(max)
-1.34V    113.4mA    130.6mA    100.3mA
-1.12V    63.6mA     79.97mA    54.13mA
-1.02V    43.09mA    58.06mA    35.43mA
-960mV    32.23mA    45.56mA    26.09mA
-920mV    25.85mA    37.67mA    21.83mA
-880mV    20.51mA    30.29mA    19.41mA
-800mV    14.34mA    18.1mA     16.31mA
-740mV    12.25mA    12.5mA     14.24mA
-680mV    10.64mA    9.841mA    12.32mA
-440mV    6.958mA    6.593mA    7.468mA
675mV     0A         NA         NA
2.7V      0A         0A         0A
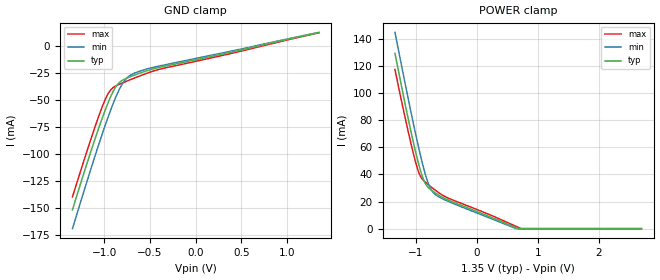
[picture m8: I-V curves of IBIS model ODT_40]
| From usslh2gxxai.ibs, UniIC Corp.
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|   Model ODT_40
[Model]  ODT_40
Model_type Input
Vinl =   0.54000000V
Vinh =   0.81000000V
C_comp   1.6290pF   1.6100pF   1.6540pF
[Temperature Range]   25.0000   95.0000   -40.0
[Voltage Range]   1.3500V   1.2830V   1.4500V
[GND_clamp]
|Voltage   I(typ)   I(min)   I(max)
-1.35V    -151.8mA   -169.3mA   -139.8mA
-1.2V     -111.1mA   -127.9mA   -99.69mA
-1.11V    -87.88mA   -103.7mA   -76.58mA
-1.05V    -73.03mA   -88.1mA    -62.06mA
-990mV    -58.98mA   -73.07mA   -49.2mA
-930mV    -46.44mA   -58.92mA   -40.36mA
-870mV    -36.95mA   -46.18mA   -36.63mA
-810mV    -31.97mA   -35.83mA   -34.38mA
-750mV    -29.46mA   -29.14mA   -32.26mA
-660mV    -26.49mA   -24.63mA   -29.17mA
-450mV    -20.72mA   -19.34mA   -22.7mA
1.35V     12.7mA     12.8mA     12.37mA
[POWER_clamp]
|Voltage   I(typ)   I(min)   I(max)
-1.34V    129.3mA    144.8mA    117.4mA
-1.1V     76.21mA    90.87mA    67.12mA
-1.02V    60.08mA    73.74mA    52.14mA
-960mV    49.12mA    61.45mA    42.71mA
-920mV    42.63mA    53.66mA    38.4mA
-880mV    37.14mA    46.35mA    35.91mA
-800mV    30.66mA    34.12mA    32.68mA
-740mV    28.29mA    28.3mA     30.49mA
-680mV    26.36mA    25.27mA    28.4mA
-460mV    20.99mA    19.97mA    22.39mA
675mV     0A         NA         NA
2.7V      0A         0A         0A
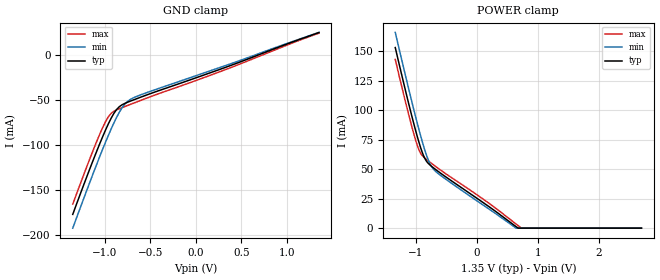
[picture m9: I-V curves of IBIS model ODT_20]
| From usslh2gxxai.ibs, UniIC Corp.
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|   Model ODT_20
[Model]  ODT_20
Model_type Input
Vinl =   0.54000000V
Vinh =   0.81000000V
C_comp   1.6290pF   1.6100pF   1.6540pF
[Temperature Range]   25.0000   95.0000   -40.0
[Voltage Range]   1.3500V   1.2830V   1.4500V
[GND_clamp]
|Voltage   I(typ)   I(min)   I(max)
-1.35V    -176.9mA   -192.2mA   -165.5mA
-1.11V    -112.5mA   -127.1mA   -101.4mA
-1.05V    -97.31mA   -111.5mA   -86.71mA
-990mV    -82.97mA   -96.44mA   -73.67mA
-930mV    -70.13mA   -82.14mA   -64.62mA
-870mV    -60.35mA   -69.15mA   -60.69mA
-810mV    -55.06mA   -58.46mA   -58.2mA
-750mV    -52.21mA   -51.37mA   -55.83mA
-690mV    -49.83mA   -47.52mA   -53.47mA
-540mV    -44.11mA   -41.53mA   -47.63mA
300mV     -14.29mA   -12.27mA   -16.84mA
1.35V     25.34mA    25.54mA    24.69mA
[POWER_clamp]
|Voltage   I(typ)   I(min)   I(max)
-1.34V    153.2mA    166.1mA    143.2mA
-1.1V     101.6mA    114mA      92.39mA
-1.02V    85.55mA    97.33mA    77.18mA
-960mV    74.41mA    85.32mA    67.61mA
-920mV    67.71mA    77.67mA    63.21mA
-880mV    62.01mA    70.43mA    60.64mA
-800mV    55.04mA    58.09mA    57.2mA
-740mV    52.26mA    51.89mA    54.81mA
-640mV    48.29mA    46.49mA    50.91mA
200mV     18.16mA    16.15mA    21.03mA
674.9mV   0A         NA         NA
2.7V      0A         0A         0A
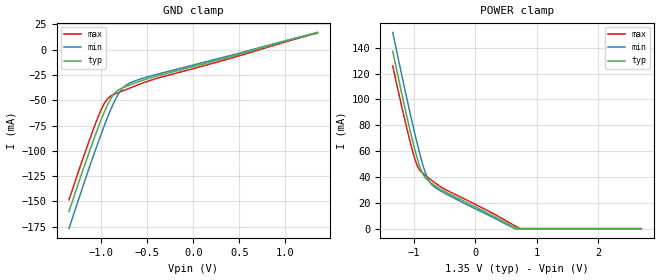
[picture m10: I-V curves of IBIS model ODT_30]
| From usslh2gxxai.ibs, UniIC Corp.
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|   Model ODT_30
[Model]  ODT_30
Model_type Input
Vinl =   0.54000000V
Vinh =   0.81000000V
C_comp   1.6290pF   1.6100pF   1.6540pF
[Temperature Range]   25.0000   95.0000   -40.0
[Voltage Range]   1.3500V   1.2830V   1.4500V
[GND_clamp]
|Voltage   I(typ)   I(min)   I(max)
-1.35V    -160.1mA   -176.9mA   -148.4mA
-1.11V    -96.08mA   -111.5mA   -84.87mA
-1.05V    -81.13mA   -95.91mA   -70.29mA
-990mV    -66.99mA   -80.86mA   -57.37mA
-960mV    -60.41mA   -73.63mA   -52.2mA
-930mV    -54.35mA   -66.67mA   -48.45mA
-870mV    -44.76mA   -53.85mA   -44.66mA
-810mV    -39.67mA   -43.38mA   -42.33mA
-750mV    -37.05mA   -36.56mA   -40.13mA
-660mV    -33.9mA    -31.82mA   -36.89mA
-480mV    -28.26mA   -26.43mA   -30.8mA
1.35V     16.92mA    17.06mA    16.48mA
[POWER_clamp]
|Voltage   I(typ)   I(min)   I(max)
-1.34V    137.3mA    151.9mA    126mA
-1.1V     84.67mA    98.56mA    75.55mA
-1.02V    68.57mA    81.6mA     60.49mA
-960mV    57.56mA    69.4mA     51.01mA
-920mV    51mA       61.66mA    46.67mA
-880mV    45.44mA    54.37mA    44.16mA
-800mV    38.8mA     42.12mA    40.86mA
-740mV    36.29mA    36.18mA    38.6mA
-660mV    33.55mA    32.19mA    35.72mA
-320mV    24.52mA    23.11mA    26.4mA
675mV     0A         NA         NA
2.7V      0A         0A         0A
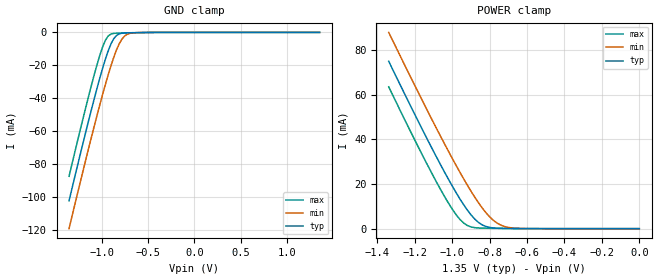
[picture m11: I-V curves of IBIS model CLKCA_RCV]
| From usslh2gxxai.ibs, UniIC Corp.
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|   Model CLKCA_RCV
[Model]  CLKCA_RCV
Model_type Input
Vinl =   0.54000000V
Vinh =   0.81000000V
C_comp   0.8303pF   0.8268pF   0.8502pF
[Temperature Range]   25.0000   95.0000   -40.0
[Voltage Range]   1.3500V   1.2830V   1.4500V
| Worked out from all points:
|   GND clamp passes 1 mA (typ) near -0.81 V on its own axis
|   POWER clamp passes 1 mA (typ) near -0.82 V on its own axis
[GND_clamp]
|Voltage   I(typ)   I(min)   I(max)
-1.35V    -102mA     -118.9mA   -87.16mA
-1.11V    -47mA      -63.74mA   -32.26mA
-1.05V    -34.12mA   -50.59mA   -19.81mA
-990mV    -22.04mA   -37.92mA   -9.042mA
-960mV    -16.49mA   -31.85mA   -4.95mA
-930mV    -11.47mA   -26.01mA   -2.28mA
-870mV    -3.95mA    -15.35mA   -630.3uA
-810mV    -922.2uA   -6.956mA   -431.8uA
-750mV    -341.2uA   -2.137mA   -349.4uA
-690mV    -218uA     -531.1uA   -276.3uA
-570mV    -96.46uA   -71.21uA   -143uA
1.35V     257.6pA    283.7pA    272.4pA
[POWER_clamp]
|Voltage   I(typ)   I(min)   I(max)
-1.34V    75.01mA    87.96mA    63.55mA
-1.22V    54.47mA    67.45mA    42.99mA
-1.1V     34.59mA    47.45mA    23.31mA
-1.04V    25.11mA    37.76mA    14.2mA
-980mV    16.21mA    28.4mA     6.314mA
-940mV    10.82mA    22.44mA    2.572mA
-880mV    4.308mA    14.14mA    450.3uA
-840mV    1.685mA    9.283mA    235.2uA
-780mV    312.9uA    3.713mA    152.1uA
-720mV    93.05uA    944.1uA    102uA
-660mV    42.22uA    183.2uA    60.69uA
0V        257.6pA    218.2pA    388.1pA
